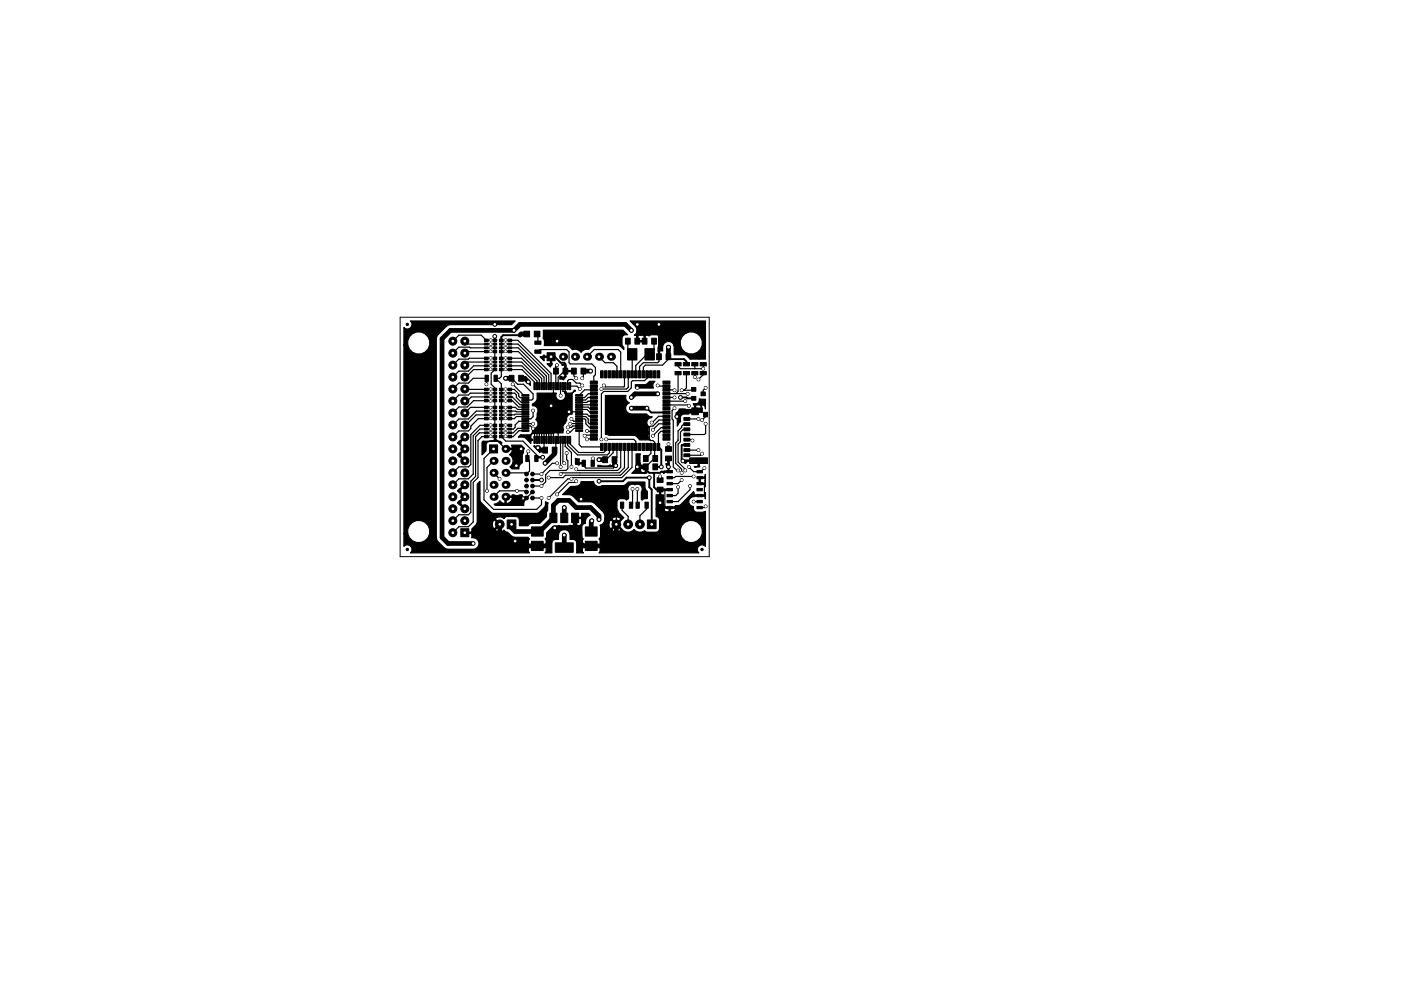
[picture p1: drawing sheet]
<svg xmlns="http://www.w3.org/2000/svg" width="297mm" height="210mm" viewBox="0 0 297 210" stroke-linecap="round" stroke-linejoin="round" font-family="sans-serif">
<path d="M84.8 67.3h65.6v50.8h-65.6z" fill="none" stroke="#000" stroke-width=".21"/>
<g fill="#000" stroke="#000" stroke-width=".21">
<path d="M102.7 75.8h.8v.5h-.8zM102.7 77.4h.8v.4h-.8zM102.7 76.6h.8v.4h-.8zM102.7 78.2h.8v.5h-.8zM102.7 72h.8v.5h-.8zM102.7 73.6h.8v.4h-.8zM102.7 72.8h.8v.4h-.8zM102.7 74.4h.8v.5h-.8zM102.8 79.6h.7v1.3h-.7zM104.5 76.6h.8v.4h-.8zM104.5 75.8h.8v.5h-.8zM104.5 77.4h.8v.4h-.8z"/>
<path d="M104.5 78.2h.8v.5h-.8zM104.5 72.8h.8v.4h-.8zM104.5 72h.8v.5h-.8zM104.5 73.6h.8v.4h-.8zM104.5 74.4h.8v.5h-.8zM104.7 79.6h.7v1.3h-.7zM105.9 77.4h.8v.4h-.8zM105.9 78.2h.8v.5h-.8zM105.9 76.6h.8v.4h-.8zM105.9 75.8h.8v.5h-.8zM105.9 73.6h.8v.4h-.8zM105.9 74.4h.8v.5h-.8z"/>
<path d="M105.9 72.8h.8v.4h-.8zM105.9 72h.8v.5h-.8zM107.7 78.2h.8v.5h-.8zM107.7 76.6h.8v.4h-.8zM107.7 77.4h.8v.4h-.8zM107.7 75.8h.8v.5h-.8zM107.7 74.4h.8v.5h-.8zM107.7 72.8h.8v.4h-.8zM107.7 73.6h.8v.4h-.8zM107.7 72h.8v.5h-.8zM111.1 70.3h1.2v1.2h-1.2zM113.3 70.3h1.2v1.2h-1.2z"/>
<path d="M113.4 74.3h1.3v.7h-1.3zM113.4 72.4h1.3v.7h-1.3zM117.4 78.1h1v1.3h-1zM116 74.8h1.7v1.7h-1.7zM119.4 78.1h1v1.3h-1zM121.2 78.1h1v1.3h-1zM123.2 78.1h1v1.3h-1zM127.3 78.7h.6v1.5h-.6zM128.1 78.7h.6v1.5h-.6zM128.9 78.7h.6v1.5h-.6zM129.7 78.7h.6v1.5h-.6zM130.5 78.7h.6v1.5h-.6z"/>
<path d="M131.3 78.7h.6v1.5h-.6zM132.1 78.7h.6v1.5h-.6zM132.6 71.8h1v1.2h-1zM132.9 78.7h.6v1.5h-.6zM133 74h2v2.4h-2zM133.7 78.7h.6v1.5h-.6zM134.5 78.7h.6v1.5h-.6zM134.6 71.8h1v1.2h-1zM135.3 78.7h.6v1.5h-.6zM136.1 78.7h.6v1.5h-.6zM136.7 74h2v2.4h-2zM136.9 78.7h.6v1.5h-.6z"/>
<path d="M136.2 71.8h1v1.2h-1zM137.7 78.7h.6v1.5h-.6zM138.5 78.7h.6v1.5h-.6zM138.2 71.8h1v1.2h-1zM139.3 78.7h.6v1.5h-.6zM139.2 75.1h1v1.2h-1zM141.2 75.1h1v1.2h-1zM143.1 76.9h1.3v.7h-1.3zM143.1 78.8h1.3v.7h-1.3zM144.9 76.9h1.3v.7h-1.3zM144.9 78.8h1.3v.7h-1.3zM146.7 76.9h1.3v.7h-1.3z"/>
<path d="M146.7 78.8h1.3v.7h-1.3zM148.4 76.9h1.3v.7h-1.3zM148.4 78.8h1.3v.7h-1.3zM102.7 86.2h.8v.5h-.8zM102.7 87.8h.8v.4h-.8zM102.7 87h.8v.4h-.8zM102.7 88.6h.8v.5h-.8zM102.7 82.4h.8v.5h-.8zM102.7 84h.8v.4h-.8zM102.7 83.2h.8v.4h-.8zM102.7 84.8h.8v.5h-.8zM102.7 90h.8v.5h-.8z"/>
<path d="M102.7 91.6h.8v.4h-.8zM102.7 90.8h.8v.4h-.8zM102.7 92.4h.8v.5h-.8zM103.8 94.4h1.7v1.7h-1.7zM104.5 87h.8v.4h-.8zM104.5 86.2h.8v.5h-.8zM104.5 87.8h.8v.4h-.8zM104.5 88.6h.8v.5h-.8zM104.5 83.2h.8v.4h-.8zM104.5 82.4h.8v.5h-.8zM104.5 84h.8v.4h-.8zM104.5 84.8h.8v.5h-.8z"/>
<path d="M104.5 90.8h.8v.4h-.8zM104.5 90h.8v.5h-.8zM104.5 91.6h.8v.4h-.8zM104.5 92.4h.8v.5h-.8zM105.9 87.8h.8v.4h-.8zM105.9 88.6h.8v.5h-.8zM105.9 87h.8v.4h-.8zM105.9 86.2h.8v.5h-.8zM105.9 84h.8v.4h-.8zM105.9 84.8h.8v.5h-.8zM105.9 83.2h.8v.4h-.8zM105.9 82.4h.8v.5h-.8z"/>
<path d="M105.9 91.6h.8v.4h-.8zM105.9 92.4h.8v.5h-.8zM105.9 90.8h.8v.4h-.8zM105.9 90h.8v.5h-.8zM108 79.6h1v1.3h-1zM107.7 88.6h.8v.5h-.8zM107.7 87h.8v.4h-.8zM107.7 87.8h.8v.4h-.8zM107.7 86.2h.8v.5h-.8zM107.7 84.8h.8v.5h-.8zM107.7 83.2h.8v.4h-.8zM107.7 84h.8v.4h-.8z"/>
<path d="M107.7 82.4h.8v.5h-.8zM107.7 92.4h.8v.5h-.8zM107.7 90.8h.8v.4h-.8zM107.7 91.6h.8v.4h-.8zM107.7 90h.8v.5h-.8zM110 79.6h1v1.3h-1zM110.6 83.7h1.5v.3h-1.5zM110.6 84.2h1.5v.3h-1.5zM110.6 84.7h1.5v.3h-1.5zM110.6 85.2h1.5v.3h-1.5zM110.6 85.7h1.5v.3h-1.5zM110.6 86.2h1.5v.3h-1.5z"/>
<path d="M110.6 86.7h1.5v.3h-1.5zM110.6 87.2h1.5v.3h-1.5zM110.6 87.7h1.5v.3h-1.5zM110.6 88.2h1.5v.3h-1.5zM110.6 88.7h1.5v.3h-1.5zM110.6 89.2h1.5v.3h-1.5zM110.6 89.7h1.5v.3h-1.5zM110.6 90.2h1.5v.3h-1.5zM110.6 90.7h1.5v.3h-1.5zM110.6 91.2h1.5v.3h-1.5zM111.5 96.6h.7v1.3h-.7zM113.2 92.6h.3v1.5h-.3z"/>
<path d="M113.2 81.2h.3v1.5h-.3zM113.7 92.6h.3v1.5h-.3zM113.7 81.2h.3v1.5h-.3zM113.4 96.6h.7v1.3h-.7zM114.2 92.6h.3v1.5h-.3zM114.2 81.2h.3v1.5h-.3zM114.7 92.6h.3v1.5h-.3zM114.7 81.2h.3v1.5h-.3zM115.2 92.6h.3v1.5h-.3zM115.2 81.2h.3v1.5h-.3zM115.7 92.6h.3v1.5h-.3zM115.7 81.2h.3v1.5h-.3z"/>
<path d="M115.1 94.9h1v1.2h-1zM116.2 92.6h.3v1.5h-.3zM116.2 81.2h.3v1.5h-.3zM116.7 92.6h.3v1.5h-.3zM116.7 81.2h.3v1.5h-.3zM117.2 92.6h.3v1.5h-.3zM117.2 81.2h.3v1.5h-.3zM117.7 92.6h.3v1.5h-.3zM117.7 81.2h.3v1.5h-.3zM117.1 94.9h1v1.2h-1zM118.2 92.6h.3v1.5h-.3zM118.2 81.2h.3v1.5h-.3z"/>
<path d="M118.7 92.6h.3v1.5h-.3zM118.7 81.2h.3v1.5h-.3zM119.2 92.6h.3v1.5h-.3zM119.2 81.2h.3v1.5h-.3zM119.7 92.6h.3v1.5h-.3zM119.7 81.2h.3v1.5h-.3zM120.2 92.6h.3v1.5h-.3zM120.2 81.2h.3v1.5h-.3zM120.7 92.6h.3v1.5h-.3zM120.7 81.2h.3v1.5h-.3zM122 91.2h1.5v.3h-1.5zM122 90.7h1.5v.3h-1.5z"/>
<path d="M122 90.2h1.5v.3h-1.5zM122 89.7h1.5v.3h-1.5zM122 89.2h1.5v.3h-1.5zM122 88.7h1.5v.3h-1.5zM122 88.2h1.5v.3h-1.5zM122 87.7h1.5v.3h-1.5zM122 87.2h1.5v.3h-1.5zM122 86.7h1.5v.3h-1.5zM122 86.2h1.5v.3h-1.5zM122 85.7h1.5v.3h-1.5zM122 85.2h1.5v.3h-1.5zM122 84.7h1.5v.3h-1.5z"/>
<path d="M122 84.2h1.5v.3h-1.5zM122 83.7h1.5v.3h-1.5zM123.4 97.6h.7v1.3h-.7zM125.3 97.6h.7v1.3h-.7zM125.2 80.8h1.5v.6h-1.5zM125.2 81.6h1.5v.6h-1.5zM125.2 82.4h1.5v.6h-1.5zM125.2 83.2h1.5v.6h-1.5zM125.2 84h1.5v.6h-1.5zM125.2 84.8h1.5v.6h-1.5zM125.2 85.6h1.5v.6h-1.5zM125.2 86.4h1.5v.6h-1.5z"/>
<path d="M125.2 87.2h1.5v.6h-1.5zM125.2 88h1.5v.6h-1.5zM125.2 88.8h1.5v.6h-1.5zM125.2 89.6h1.5v.6h-1.5zM125.2 90.4h1.5v.6h-1.5zM125.2 91.2h1.5v.6h-1.5zM125.2 92h1.5v.6h-1.5zM125.2 92.8h1.5v.6h-1.5zM127.3 94.1h.6v1.5h-.6zM127.8 96.9h1v1.3h-1zM128.1 94.1h.6v1.5h-.6zM128.9 94.1h.6v1.5h-.6z"/>
<path d="M129.7 94.1h.6v1.5h-.6zM129.8 96.9h1v1.3h-1zM130.5 94.1h.6v1.5h-.6zM131.3 94.1h.6v1.5h-.6zM132.1 94.1h.6v1.5h-.6zM132.9 94.1h.6v1.5h-.6zM133.7 94.1h.6v1.5h-.6zM134.5 94.1h.6v1.5h-.6zM135.3 94.1h.6v1.5h-.6zM136.1 94.1h.6v1.5h-.6zM136.4 96.7h1v1.2h-1zM136.9 94.1h.6v1.5h-.6z"/>
<path d="M136.4 98.4h1v1.3h-1zM137.7 94.1h.6v1.5h-.6zM138.4 96.7h1v1.2h-1zM138.5 94.1h.6v1.5h-.6zM139.3 94.1h.6v1.5h-.6zM138.4 98.4h1v1.3h-1zM141.1 94.8h1.3v1h-1.3zM141.1 96.8h1.3v1h-1.3zM141.4 99.8h1.2v.5h-1.2zM140.6 92.8h1.5v.6h-1.5zM140.6 92h1.5v.6h-1.5zM140.6 91.2h1.5v.6h-1.5z"/>
<path d="M140.6 90.4h1.5v.6h-1.5zM140.6 89.6h1.5v.6h-1.5zM140.6 88.8h1.5v.6h-1.5zM140.6 88h1.5v.6h-1.5zM140.6 87.2h1.5v.6h-1.5zM140.6 86.4h1.5v.6h-1.5zM140.6 85.6h1.5v.6h-1.5zM140.6 84.8h1.5v.6h-1.5zM140.6 84h1.5v.6h-1.5zM140.6 83.2h1.5v.6h-1.5zM140.6 82.4h1.5v.6h-1.5zM140.6 81.6h1.5v.6h-1.5z"/>
<path d="M140.6 80.8h1.5v.6h-1.5zM145 88.6h1.2v.6h-1.2zM145 89.7h1.2v.6h-1.2zM145 90.8h1.2v.6h-1.2zM145 91.9h1.2v.6h-1.2zM145 93h1.2v.6h-1.2zM145 94.1h1.2v.6h-1.2zM145 95.2h1.2v.6h-1.2zM145 96.3h1.2v.6h-1.2zM146.6 82.2h.9v.8h-.9zM146.6 84.1h.9v.8h-.9zM147.8 99.8h1.1v.5h-1.1z"/>
<path d="M146.7 86.5h1.4v1.5h-1.4zM148.6 83.2h.9v.8h-.9zM148.3 86.5h.6v1h-.6zM146.2 97.1h3.8v1.2h-3.8zM149.2 87.5h.8v.9h-.8zM97.7 112.2h1.7v1.7h-1.7zM107.5 110.3h1.9v1.9h-1.9zM112.7 111.8h2.5v1.9h-2.5zM112.7 114.8h2.5v2h-2.5zM116.6 108.9h1.5v2h-1.5zM117.7 115.2h3.8v2h-3.8zM118.9 108.9h1.5v2h-1.5z"/>
<path d="M121.2 108.9h1.5v2h-1.5zM124.1 111.8h2.5v1.9h-2.5zM124.1 114.8h2.5v2h-2.5zM131.5 106.5h.7v1.3h-.7zM133.4 106.5h.7v1.3h-.7zM134.8 106.5h.7v1.3h-.7zM136.7 106.5h.7v1.3h-.7zM137.3 110.3h1.8v1.9h-1.8zM139.3 101.4h1.3v1h-1.3zM139.3 103.4h1.3v1h-1.3zM141.4 101.1h1.2v.5h-1.2zM141.4 102.4h1.2v.5h-1.2z"/>
<path d="M141.4 103.6h1.2v.5h-1.2zM141.4 104.9h1.2v.5h-1.2zM141.4 106.2h1.2v.5h-1.2zM141.4 107.4h1.2v.5h-1.2zM147.8 107.4h1.1v.5h-1.1zM147.8 106.2h1.1v.5h-1.1zM147.8 103.6h1.1v.5h-1.1zM147.8 102.4h1.1v.5h-1.1zM147.8 101.1h1.1v.5h-1.1zM147.8 104.9h1.1v.5h-1.1z"/>
<circle cx="86.4" cy="68.8" r=".25"/>
<circle cx="96" cy="74.9" r=".85"/>
<circle cx="96" cy="72.4" r=".85"/>
<circle cx="96" cy="77.5" r=".85"/>
<circle cx="98.6" cy="72.4" r=".85"/>
<circle cx="98.6" cy="74.9" r=".85"/>
<circle cx="98.6" cy="77.5" r=".85"/>
<circle cx="104" cy="72.1" r=".25"/>
<circle cx="104" cy="78.4" r=".25"/>
<circle cx="104" cy="73.8" r=".25"/>
<circle cx="104" cy="73" r=".25"/>
<circle cx="104" cy="75.9" r=".25"/>
<circle cx="104" cy="74.5" r=".25"/>
<circle cx="104" cy="77.6" r=".25"/>
<circle cx="104" cy="76.8" r=".25"/>
<circle cx="104.9" cy="71.4" r=".4"/>
<circle cx="104.9" cy="68.8" r=".4"/>
<circle cx="107.2" cy="75.9" r=".25"/>
<circle cx="107.2" cy="73.8" r=".25"/>
<circle cx="107.2" cy="76.8" r=".25"/>
<circle cx="107.2" cy="77.6" r=".25"/>
<circle cx="107.2" cy="73" r=".25"/>
<circle cx="107.2" cy="72.1" r=".25"/>
<circle cx="107.2" cy="74.5" r=".25"/>
<circle cx="107.2" cy="78.4" r=".25"/>
<circle cx="109" cy="70.1" r=".4"/>
<circle cx="118.1" cy="77.5" r=".3"/>
<circle cx="118.1" cy="72.4" r=".3"/>
<circle cx="125.2" cy="78.7" r=".4"/>
<circle cx="133.9" cy="70.1" r=".4"/>
<circle cx="135.1" cy="68.8" r=".4"/>
<circle cx="139.7" cy="68.8" r=".4"/>
<circle cx="141.7" cy="73.7" r=".4"/>
<circle cx="149.1" cy="78.2" r=".3"/>
<circle cx="96" cy="80" r=".85"/>
<circle cx="96" cy="87.6" r=".85"/>
<circle cx="96" cy="92.7" r=".85"/>
<circle cx="96" cy="90.2" r=".85"/>
<circle cx="96" cy="97.8" r=".85"/>
<circle cx="96" cy="82.5" r=".85"/>
<circle cx="96" cy="95.2" r=".85"/>
<circle cx="96" cy="85.1" r=".85"/>
<circle cx="98.6" cy="85.1" r=".85"/>
<circle cx="98.6" cy="92.7" r=".85"/>
<circle cx="98.6" cy="80" r=".85"/>
<circle cx="98.6" cy="97.8" r=".85"/>
<circle cx="98.6" cy="82.5" r=".85"/>
<circle cx="98.6" cy="87.6" r=".85"/>
<circle cx="98.6" cy="90.2" r=".85"/>
<circle cx="98.6" cy="95.2" r=".85"/>
<circle cx="103.1" cy="81.5" r=".3"/>
<circle cx="104" cy="88" r=".25"/>
<circle cx="104" cy="88.8" r=".25"/>
<circle cx="104" cy="84.2" r=".25"/>
<circle cx="104" cy="82.5" r=".25"/>
<circle cx="104" cy="92.6" r=".25"/>
<circle cx="104" cy="83.4" r=".25"/>
<circle cx="104" cy="91.1" r=".25"/>
<circle cx="104" cy="85.1" r=".25"/>
<circle cx="104" cy="91.8" r=".25"/>
<circle cx="104" cy="86.5" r=".25"/>
<circle cx="104" cy="90.2" r=".25"/>
<circle cx="104" cy="87.2" r=".25"/>
<circle cx="107.2" cy="92.6" r=".25"/>
<circle cx="107.2" cy="88" r=".25"/>
<circle cx="107.2" cy="91.8" r=".25"/>
<circle cx="107.2" cy="88.8" r=".25"/>
<circle cx="107.2" cy="86.5" r=".25"/>
<circle cx="107.2" cy="83.4" r=".25"/>
<circle cx="107.2" cy="91.1" r=".25"/>
<circle cx="107.2" cy="90.2" r=".25"/>
<circle cx="107.2" cy="87.2" r=".25"/>
<circle cx="107.2" cy="85.1" r=".25"/>
<circle cx="107.2" cy="84.2" r=".25"/>
<circle cx="107.2" cy="82.5" r=".25"/>
<circle cx="107.2" cy="80.3" r=".4"/>
<circle cx="108.7" cy="81.5" r=".3"/>
<circle cx="109.5" cy="98.8" r=".3"/>
<circle cx="110.5" cy="95.2" r=".3"/>
<circle cx="112" cy="81" r=".4"/>
<circle cx="112" cy="95.8" r=".3"/>
<circle cx="113" cy="87.1" r=".3"/>
<circle cx="113" cy="89.9" r=".3"/>
<circle cx="113" cy="90.9" r=".3"/>
<circle cx="114" cy="95" r=".4"/>
<circle cx="115.1" cy="97" r=".4"/>
<circle cx="115.6" cy="98.3" r=".4"/>
<circle cx="116.8" cy="86.1" r=".3"/>
<circle cx="118.1" cy="98.3" r=".3"/>
<circle cx="118.9" cy="99.1" r=".3"/>
<circle cx="118.9" cy="83.9" r=".3"/>
<circle cx="119.6" cy="98.3" r=".3"/>
<circle cx="120.1" cy="96.1" r=".3"/>
<circle cx="120.4" cy="91.7" r=".3"/>
<circle cx="120.4" cy="90.7" r=".3"/>
<circle cx="120.7" cy="87.4" r=".3"/>
<circle cx="120.9" cy="89.9" r=".3"/>
<circle cx="121.2" cy="99.1" r=".3"/>
<circle cx="121.2" cy="88.9" r=".3"/>
<circle cx="122.2" cy="99.6" r=".3"/>
<circle cx="122.2" cy="80.3" r=".3"/>
<circle cx="122.9" cy="82.5" r=".3"/>
<circle cx="123.4" cy="80.3" r=".3"/>
<circle cx="123.4" cy="81.8" r=".3"/>
<circle cx="124" cy="92.5" r=".3"/>
<circle cx="124.5" cy="93.2" r=".3"/>
<circle cx="124.5" cy="91.4" r=".3"/>
<circle cx="125.7" cy="97.3" r=".3"/>
<circle cx="127" cy="97.5" r=".4"/>
<circle cx="127.5" cy="93.2" r=".3"/>
<circle cx="127.5" cy="82.5" r=".3"/>
<circle cx="128" cy="81.8" r=".3"/>
<circle cx="128.5" cy="93.2" r=".3"/>
<circle cx="130.6" cy="98.8" r=".4"/>
<circle cx="133.9" cy="84.3" r=".4"/>
<circle cx="133.9" cy="86.6" r=".4"/>
<circle cx="135.1" cy="99.1" r=".4"/>
<circle cx="135.1" cy="82.3" r=".3"/>
<circle cx="137.2" cy="86.6" r=".4"/>
<circle cx="138.2" cy="89.7" r=".3"/>
<circle cx="138.4" cy="91.2" r=".3"/>
<circle cx="138.4" cy="92.5" r=".3"/>
<circle cx="139.4" cy="83.6" r=".4"/>
<circle cx="139.4" cy="81.8" r=".3"/>
<circle cx="140.2" cy="99.1" r=".4"/>
<circle cx="141.7" cy="99.1" r=".4"/>
<circle cx="141.7" cy="94.2" r=".3"/>
<circle cx="143" cy="86.6" r=".3"/>
<circle cx="143" cy="82.8" r=".3"/>
<circle cx="143" cy="84.3" r=".3"/>
<circle cx="143.5" cy="88.4" r=".4"/>
<circle cx="143.8" cy="99.8" r=".3"/>
<circle cx="144.3" cy="84.3" r=".4"/>
<circle cx="144.5" cy="82.8" r=".3"/>
<circle cx="144.8" cy="97.8" r=".4"/>
<circle cx="145.3" cy="85.1" r=".3"/>
<circle cx="145.3" cy="99.8" r=".3"/>
<circle cx="145.8" cy="83.6" r=".3"/>
<circle cx="146.1" cy="99.1" r=".3"/>
<circle cx="146.1" cy="86.1" r=".3"/>
<circle cx="146.8" cy="93.5" r=".3"/>
<circle cx="147.3" cy="80" r=".3"/>
<circle cx="148.1" cy="95.5" r=".3"/>
<circle cx="148.1" cy="88.9" r=".3"/>
<circle cx="148.1" cy="80.5" r=".3"/>
<circle cx="148.8" cy="96.3" r=".3"/>
<circle cx="148.8" cy="89.1" r=".3"/>
<circle cx="149.4" cy="99.3" r=".3"/>
<circle cx="149.6" cy="89.9" r=".3"/>
<circle cx="149.6" cy="82.3" r=".3"/>
<circle cx="86.4" cy="116.6" r=".25"/>
<circle cx="96" cy="100.3" r=".85"/>
<circle cx="96" cy="110.5" r=".85"/>
<circle cx="96" cy="107.9" r=".85"/>
<circle cx="96" cy="105.4" r=".85"/>
<circle cx="96" cy="113" r=".85"/>
<circle cx="96" cy="102.9" r=".85"/>
<circle cx="98.6" cy="107.9" r=".85"/>
<circle cx="98.6" cy="110.5" r=".85"/>
<circle cx="98.6" cy="100.3" r=".85"/>
<circle cx="98.6" cy="105.4" r=".85"/>
<circle cx="98.6" cy="102.9" r=".85"/>
<circle cx="100.3" cy="115.3" r=".3"/>
<circle cx="103.3" cy="104.1" r=".3"/>
<circle cx="105.9" cy="101.6" r=".3"/>
<circle cx="106" cy="111.2" r=".92"/>
<circle cx="109.2" cy="114.8" r=".3"/>
<circle cx="109.6" cy="104.1" r=".3"/>
<circle cx="111.6" cy="105.7" r=".39"/>
<circle cx="111.6" cy="101.8" r=".39"/>
<circle cx="111.6" cy="104.4" r=".39"/>
<circle cx="111.6" cy="100.6" r=".39"/>
<circle cx="111.6" cy="103.1" r=".39"/>
<circle cx="112.9" cy="100.6" r=".39"/>
<circle cx="112.9" cy="105.7" r=".39"/>
<circle cx="112.9" cy="103.1" r=".39"/>
<circle cx="112.9" cy="101.8" r=".39"/>
<circle cx="112.9" cy="104.4" r=".39"/>
<circle cx="114.8" cy="101.8" r=".4"/>
<circle cx="114.8" cy="103.1" r=".3"/>
<circle cx="114.8" cy="105.7" r=".3"/>
<circle cx="114.8" cy="100.6" r=".3"/>
<circle cx="116.3" cy="101.3" r=".3"/>
<circle cx="116.3" cy="105.7" r=".3"/>
<circle cx="117.6" cy="112" r=".3"/>
<circle cx="118.1" cy="104.9" r=".3"/>
<circle cx="118.9" cy="100.6" r=".3"/>
<circle cx="119.6" cy="113.5" r=".4"/>
<circle cx="119.6" cy="107.7" r=".4"/>
<circle cx="121.2" cy="101.6" r=".3"/>
<circle cx="122.2" cy="102.1" r=".3"/>
<circle cx="123.2" cy="105.9" r=".3"/>
<circle cx="125.5" cy="110.5" r=".4"/>
<circle cx="127" cy="110.2" r=".4"/>
<circle cx="127" cy="102.1" r=".4"/>
<circle cx="130.7" cy="111.2" r=".92"/>
<circle cx="133.2" cy="111.2" r=".92"/>
<circle cx="134.1" cy="103.8" r=".3"/>
<circle cx="135.1" cy="103.8" r=".3"/>
<circle cx="135.7" cy="111.2" r=".92"/>
<circle cx="137.7" cy="101.3" r=".4"/>
<circle cx="140" cy="101.1" r=".3"/>
<circle cx="140" cy="106.7" r=".3"/>
<circle cx="143.8" cy="103.4" r=".3"/>
<circle cx="144.5" cy="101.8" r=".3"/>
<circle cx="144.5" cy="100.3" r=".3"/>
<circle cx="146.3" cy="103.1" r=".3"/>
<circle cx="147.1" cy="101.1" r=".3"/>
<circle cx="147.1" cy="106.4" r=".3"/>
<circle cx="148.8" cy="116.6" r=".25"/>
<circle cx="149.6" cy="107.4" r=".3"/>
</g>
<g fill="#000">
<circle cx="119.4" cy="75.7" r=".85"/>
<circle cx="121.9" cy="75.7" r=".85"/>
<circle cx="124.5" cy="75.7" r=".85"/>
<circle cx="127" cy="75.7" r=".85"/>
<circle cx="129.5" cy="75.7" r=".85"/>
<circle cx="104.6" cy="97.8" r=".85"/>
<circle cx="107.2" cy="95.2" r=".85"/>
<circle cx="107.2" cy="97.8" r=".85"/>
<circle cx="104.6" cy="100.3" r=".85"/>
<circle cx="104.6" cy="102.9" r=".85"/>
<circle cx="104.6" cy="105.4" r=".85"/>
<circle cx="107.2" cy="105.4" r=".85"/>
<circle cx="107.2" cy="102.9" r=".85"/>
<circle cx="107.2" cy="100.3" r=".85"/>
</g>
<path d="M115.1 97h-1.1l-.3 .3" fill="none" stroke="#000" stroke-width=".5"/>
<g fill="none" stroke="#000" stroke-width=".25">
<path d="M98.6 72.4l.6 .6h4.8M104 77.6h-3.6l-1.1 1.1h-2l-1.3 1.3M104 73.8l-6.7-.1-1.3 1.2M104 76.8h.1M104 76.8h-4.8l-.6 .7M104 74.5l-5.1 .1-.3 .3M104 78.4h-3.6l-1.6 1.6h-.2M104 77.6h.1M104 75.9l-6.7 .3-1.3 1.3M104 73.8h.1M104 72.1l-.9 .1-1.1-1.1h-4.7l-1.3 1.3M104.9 72.2v6.2l-.8 .8v2.3l.8 .8v10.7l2.3 2.2"/>
<path d="M106.3 72.2v7.7l-.4 .4h-.8l1.2 1.2v11.1l.9 1h3.7l2.8 2.8v.9M107.2 73h2.6l6.5 6.5v2.4M107.2 74.5l2.7 .1 5.4 5.4v1.9M107.2 72.1l2.6 .1 7 7v2.7M107.2 73.8h2.7l5.9 6v2.1M107.2 75.9l3.4 .1 4.2 4.3v1.6M107.2 76.8h3.4l3.7 3.8v1.3M107.2 77.6h3.4l3.2 3.2v1.1M107.2 78.4h3.5l2.6 2.7v.8M113.9 70.9l.1 .1v1.7M114 74.6l.5-.4h5.6l.5 .5v2.3l.3 .2h4.6l.7 .8v1.5l-.3 .3v1.3M117.9 78.7l-.1 3.2"/>
<path d="M119.9 78.7h-.3l-1.3 1.3v1.9M121.7 78.7v1.1l.5 .5M123.7 78.7v1.3l-.3 .3M124.5 75.7l1.5-1.5h5.1l.5 .5v4.7M127 75.7l1.3 1.3h1.7l.8 .7v1.7M132.4 79.4v2.6l-.1 .1h-4l-.3-.3M133.1 72.4v1.9l.9 .9v4.2M133.2 79.4v2.8l-.4 .3h-5.3M137.2 79.4v.8l-.5 .6h-2.6l-.2 .2v1.3l-.8 .8h-5.1l-.5 .5v9.6M138.7 72.4v1.9l-1 .9h-.5l-2.4 2.3v1.9M139.7 75.7v1l-.3 .3h-3l-.8 .8v1.6M141.7 75.7v.5l-1.2 1.3h-3.7l-.4 .4v1.5"/>
<path d="M143.8 77.3v.4l.5 .5h4.8v-.9M143.8 79.2v3.9l-.5 .4M145.5 79.2v3.1l-.5 .5M147.3 77.3v.9M147.3 79.2v.8M149.1 79.2v.3l-1 1M98.6 82.5h5.4M103.1 81.5l.1-1.2h-2.9l-1 1h-2l-1.3 1.2M104 87.2h-3l-1.7 1.7h-2l-1.3 1.3M104 87.2h.1M104 83.4h-4.3l-.4 .4h-2l-1.3 1.3M104 83.4h.1"/>
<path d="M104 86.5l-4.2-.1-1.2 1.2M104 90.2h-2.2l-2 2v6.3l-.5 .6h-2l-1.3 1.2M104 92.6h-1.8l-.9 .9v7.8l-1 1.1v8.3l-1 1.1h-2l-1.3 1.2M104 91.1l-2.3-.1-1.4 1.5v8.1l-1 1h-2l-1.3 1.3M104 91.8h-2.3l-.9 .8v8.5l-1 1v6.6l-.5 .5h-2l-1.3 1.3M104 88.8h-2.6l-1.6 1.6v.5l-.5 .5h-2l-1.3 1.3M104 88h-3.1l-2.1 2.2h-.2M104 84.2h-4.1l-.8 .9h-.5M104 85.1l-3.6-.1-1.3 1.4h-1.8l-1.3 1.2M104.6 95.2l-2 2.1v8.7l2 2.1h9.2l1-1v-1.4h-1.9M104.6 97.8l-1.3 1.4v4.9M107.2 87.2l4.2 .2"/>
<path d="M107.2 83.4h1.9l.4 .4v.5l1 1.1h.9M107.2 82.5l1.8 .1 1 1v.5l.3 .3h1.1M107.2 84.2h1.4l1.7 1.7h1.1M107.2 85.1l1.4-.1 1.4 1.4h1.4M107.2 86.5l2.1-.1 .4 .5h1.7M107.2 90.2h.9M108.5 80.3l1.2 1.2h1.3l2 2.1v1l-.3 .3h-1.3M108.7 81.5l2.4 2.4h.3M110 89.4h1.4M110 89.4h.1M110 89.4l-.8 .8v.5l-.3 .3-1.7 .1M110.5 95.2v2.1l-1 1v.2"/>
<path d="M111.4 90.4h1.1l.8 .8v2.1M111.4 87.9l-4.2 .1M111.4 88.4h-1.9l-.5 .4h-1.8M111.4 89.9h1.6M111.4 90.9h-1.6l-1 .9h-1.6M111.4 91.4h-1.4l-1.2 1.2h-1.6M112 95.8l-.2 .1v1.4l.5 .4v2.2l-.7 .7-.2-.3h-4.2M113 89.9h.1M113 87.1v1.3l-.5 .5h-1.1M113 90.9h5l.3 .4v2M113.8 90.9v2.4M114.3 90.9v2.4"/>
<path d="M114.8 90.9v2.4M115.3 90.9v4.4l.3 .2M115.8 90.9v2.4M116.3 90.9v2.4M116.8 90.9v2.4M117.3 81.9v2.9l.4 .4h1.8l.5-.5-.2-2.8M117.3 90.9v2.4M117.3 83.9h.1M117.8 93.3v1.9l-.2 .3M118.1 98.3h-1l-2.3 2.3h-1.9M118.8 81.9l.1 2M118.8 93.3l.1 5.8"/>
<path d="M119.3 81.9v1.2h.6M119.3 93.3v4.7l.3 .3M119.6 83.1l.4 .3M119.8 93.3l.1 1.4M119.8 94.7l1.4 1.3v3.1M120.1 96.1v1.4l.3 .3v1.6l-.4 .4h-3.4l-.9 .9v1.5l-.9 .9h-1.9M120.3 93.3v1.1l2.1 2.1h6.4l.4-.4v-1.3M120.6 87.4h.1M120.7 87.4h2.1M120.8 81.9h1.5l.6 .6M120.8 93.3v.9l1.9 1.8h5.3l.4-.4v-.8M121.2 88.9l.4 .5h1.2"/>
<path d="M122.8 87.9h1.7l.4 .4h1M122.8 90.4h-1.3l-.3 .3h-.8M122.8 85.9h3.1M122.8 86.4h1.9l.4 .3h.8M122.8 86.9h1.7l.6 .6h.8M122.8 88.4h1.4l.5 .5v.8l.3 .2h.9M122.8 89.9h-1.9M122.8 88.9h1.2l.2 .2v.8l.8 .8h.9M122.8 90.9h-1.1l-.8 .8h-.5M122.8 91.4v2.9l.5 .5h4.3M123.4 81.8l-.5-.5h-.7l-.8-.8h-.8l-.3 .3v1.1M123.8 98.3v.6l.4 .4h5.8l.6-.5"/>
<path d="M124.5 91.4l1.4 .1M125.7 97.3v1M125.9 92.3h-1.8l-.1 .2M125.9 84.3h-1.2l-.5 .6h-1.4M125.9 85.1h-1.2l-.3 .3h-1.6M125.9 83.5h-1.1l-.9 .9h-1.1M125.9 82.7h-1.9l-1.2 1.2M125.9 93.1l-1.4 .1M128.5 93.2h5.9l.4 .5v1.1M130 94.8v1.3l-1.5 1.4h-.2M130.8 94.8v2.2l-.5 .5M131.6 94.8v4.3l-.7 .7h-8.5l-.2-.2"/>
<path d="M132.4 94.8v4.4l-1.1 1.1h-12.2l-.2 .3M133.2 94.8v4.4l-1.6 1.6h-11.7l-.5 .5h-3.1M134 94.8v4.4l-2.2 2.1h-10.4l-.2 .3h-.8l-4.1 4.1M138 94.8v1.4l-1.1 1.1M139.4 81.8l.2 .1h1.7M141.3 91.5h-1.2l-.5 .5v2.8M141.3 89.1h-1.6l-1.3 1.3h-.5l-.2 .3v2.5l.2 .3h.5l.4 .3v3.4l.1 .1h-.2l-1.8 1.8M141.3 85.9h4.6l.1 .2M141.3 84.3h1.7M141.3 89.9h-1.6l-1.3 1.3M141.3 83.5l4.5 .1M141.3 82.7l1.7 .1"/>
<path d="M141.3 88.3h-1.7l-1.4 1.4M141.3 90.7h-1.1l-1.8 1.8M141.7 94.2v1.1M143 84.3h.1M143 86.6l-.5 .5v1.8l.2 .2v10l.8 .7h.3M145.3 85.1h-4M145.6 91.1h-.7l-.6 .6v2l-.5 .5v3.8l1.5 1.6v.2M145.6 90h-.6l-1.2 1.4v2.1l-.5 .5v4.3l1.2 1.3v.7M145.6 95.5h2.5M145.6 88.9h2.5M145.6 93.3h1l.2 .2M146 99.1l1.1 1h1.5l.8-.8"/>
<path d="M147.1 82.6l-.2 .2h-2.4M148.1 88.9h.1M148.6 87h-1l-.2 .3M148.8 96.3l-.3 .3h-2.9M149.6 88v.4l-.8 .7M149.6 89.9v2l-.2 .3h-3.8M149.6 82.3l-.5 .5v.8M104.6 100.3l1.3 1.3M109.2 114.8v1M111.6 104.4l-.2-.3h-5.5l-1.3 1.3M112.9 104.4l-1.3 1.3-.2-.3h-4.2M122.2 102.1l-.3 .3h-1.3l-2.5 2.5"/>
<path d="M123.2 105.9h4.8l2.7 2.7v2.6M131.9 107.2v1.1l1.3 1.2v1.7M134.1 103.8v3.1l-.3 .3M135.1 103.8v3.3l.3-.1M137.1 107.2v.8l-1.4 1.4v1.8M140 101.1v.8M141.2 103.9l-.2 .2v3.3l.2 .3h.8M142 103.9h-2v2.8M143.8 103.4v1.2l-.5 .6h-1.3M144.5 101.8l-.7 .8h-1.8M146.3 103.1v.8l-2.5 2.5h-1.8M147.1 101.1h-3.8l-.3 .2h-1"/>
<path d="M147.1 106.4h1.2M148.3 101.3v1.3h.8l.3 .3v2l-.3 .3h-.8M149.6 107.4h.1M149.6 107.4l-.2 .3h-1.1"/>
</g>
<g fill="none" stroke="#000" stroke-width=".4">
<path d="M104.9 71.4v.8M110.2 71.1h-3.5l-.4 .4v.7M116.8 75.7h.8l1.3 1.3h.7l.3 .2v1.5h1.8M116.8 75.7h.1M118.1 77.5l-.2 .2v1M135.1 68.8v3.6h1.6M135.1 68.8h.1M139.7 68.8h.1M139.7 68.8v6.9M141.7 75.7l.5 .5h2.8l.5 .5v.6M137.2 86.6l.9 .9h3.2M139.6 94.8l.6 .6v3.7h-1.3"/>
<path d="M141.7 97.3v2.5l.3 .3h-1.8l-.2 .2h-2.3l-.8-.7v-.5M144.3 84.3l2.8 .2M145.6 94.4l-1.1 .1v3l.3 .3 3.3-.1M112.9 101.8h1.9M127 102.1h5.1l.7-.8h4.9v2.1l.5 .5v7.3M138.7 100.3v3.1l.5 .5h.8M148.3 105.2h-1.5l-2.5 2.5h-2.3"/>
</g>
<g fill="none" stroke="#000" stroke-width="1">
<path d="M111.7 70.9h-1.2l-.3 .2M123.7 78.7h1.5M133.9 70.1l-1.3-1.3h-22.4l-1.2 1.3h-13.5l-1.8 1.8v42.1l1.3 1.3h5.3M141.7 73.7v2M141.7 73.7h.1M107.2 80.3h1.3M110.5 80.3h.8l.7 .7M114 95l.6 .5h1M117.6 95.5v.8l-2 2M127 97.5h1.3M130.3 97.5v1l.3 .3M133.9 86.6h3.3"/>
<path d="M135.1 99.1h1.8M139.4 83.6h-4.8l-.7 .7M147.4 87.3h-2.8l-1.1 1.1M106 111.2v3.6l.9 1h8.9l.8-.7v-2.1l1-1h4.6M119.6 107.7v2.2M119.6 113.5v2.7M121.9 109.9v1.9l1 1v2.3l.8 .7h6.3l.7-.6v-4M125.5 110.5l-.2 .1v2.2M127 110.2v-.7l-1.8-1.8h-3l-1.6-1.5h-2.2l-1.1 1v2.7l-2.9 2.9h-5.2l-.7-.8v-.8"/>
</g>
<g fill="#000" stroke="#000" stroke-width=".25">
<path d="M85.6 69.5a.98 .98 0 0 0 1.5 0 .98 .98 0 0 0-.1-1.4h22.2l-.7 .8-13.5 .1-2.1 2-.4 .9v42.1l.4 .9 1.6 1.5 5.8 .1a1.25 1.25 0 0 0 1.2-1.4 1.25 1.25 0 0 0-1.5-1v-.8l-.1-.1h-1.5v-.3h1.5l.1-.2v-.5l1.1-1.2h3.3v.6l.2 .5 .3 .1 .9-1-.9-.9-.3 .1-.2 .6h-3.3l.1-8.3 .6-.6v4.3l2.5 2.5h9.5a2.85 2.85 0 0 0 1.8-1.5l.1-1 .5 .3-.4 2.9-1.4 1.5h-2l-.4 .4h-1.9v-1.2a.74 .74 0 0 0-.7-.7h-1.9l-.5 .2-.2 .3v-.2a1.18 1.18 0 0 0-1.8 .2l1.2 1.1-1.2 1.1a1.12 1.12 0 0 0 1.8 .1l1.9 1.5 3.3 .1 .3 .3-.3 .4v.8l.2 .2h3.4l.2-.2v-.8l-.2-.4 .3-.3v-1l1.4-1.4 1.2-.1 .4 .1h1.5l.5-.2 .7 .1 .2-.1v-1.4h.3v1.4l.1 .1h.6l.5-.5v-.8l-.1-.2h-1.4v-.3h1.4l.1-.1v-.7h1.4l.4 .4-.1 .1a1.56 1.56 0 0 0-.9 1.7l-.5 .2-.2 .5v1.9l.3 .6-.2 .4v.8l.1 .2h3.5l.1-.2v-.8l-.2-.4a.96 .96 0 0 0 .3-1.1h16.9l.4 .9a2.37 2.37 0 0 0 3.9 0 2.37 2.37 0 0 0-1.5-3.7 2.37 2.37 0 0 0-2.8 2.8h-16.9v-.9h2.5v.3a1.18 1.18 0 0 0 1.8-.3l-.9-.9-.9 .9h-2.5l-.1-.9a2.65 2.65 0 0 1 1.9-.4v.6l.2 .5 .3 .1 .9-1-.9-.9-.3 .1-.2 .6h-1.2l.3-.9h1.6l.9 1 .9-1a1.09 1.09 0 0 0-1.8 0h-1.6l-.1-1.1-.2-.4-2.2-2-3-.1-1.6-1.5-1.8-.1 1.7-1.7 1.4-.1a1 1 0 0 0 .8-.9h2.7v.1a1.14 1.14 0 0 0 1.8 .7h4.4h.3l.8-.7h3.5l.1 1.4 .4 .6v1.5h-.7l-.4 .3-.1-.1v-1.6a1.04 1.04 0 0 0-.1-1.3 1.04 1.04 0 0 0-1.3-.2 1.04 1.04 0 0 0-1.3 .2 1.04 1.04 0 0 0 0 1.3v1.4l-.5 .3a1.21 1.21 0 0 0-2 .4l.1 1.6 .4 .8 1 .9-1.4 1.4 .9 1a1.65 1.65 0 0 0 2.6 .1 1.61 1.61 0 0 0 2.3 .3l.6 .3h1.8a.74 .74 0 0 0 .7-.7v-1.9l-.2-.5-.5-.2v-1.6l1.7 .1a.71 .71 0 0 0 .9 .5l.2-.2v-.6h.2v.6l.2 .2 .6-.1 .3-.5-.2-.2-3.9 .2v-3h.6l.1-.2v-1.1h2.3v.3h-2v.8l.1 .2h.5l.1 .8a2.32 2.32 0 0 0 .1 1.8h2.1l.2-.3 .9-.1 2.9-2.9 .3 .7h2.1l.2-.5v1.3l-.2-.5h-2.1l-.1 .1a1.03 1.03 0 0 0-1.2 .9 1.03 1.03 0 0 0 1 1.1 .92 .92 0 0 0 .8 1.3h1.1l.7-.2v7.4a.98 .98 0 0 0-1.5 0 .98 .98 0 0 0 .1 1.4h-21.2l.2-.4v-.8l-.1-.2h-3.5l-.1 .2v.8l.2 .4h-1.5v-2.4l-.4-.4-.9-.1a1.65 1.65 0 0 0-.8-2 1.23 1.23 0 0 0-1.7 1.1v.9h-.7a.74 .74 0 0 0-.7 .8v2.1h-1.4l.2-.4v-.8l-.2-.2h-3.4l-.2 .2v.8l.3 .4h-25.3l.2-.2a.99 .99 0 0 0-.2-1.3 .99 .99 0 0 0-1.4 .1v-2.7h.8a2.37 2.37 0 0 0 3.7 1.5 2.37 2.37 0 0 0 0-3.9 2.37 2.37 0 0 0-3.7 1.5v.9h-.8v-40h.8a2.37 2.37 0 0 0 3.7 1.5 2.37 2.37 0 0 0 0-3.9 2.37 2.37 0 0 0-3.7 1.5v.9h-.8zM114.5 75.7a.79 .79 0 0 0 .9-.4l.1 .3h1.5v1.4l.1 .2-.4 .7-.7-.7h.6l.1-.2v-1.2h-1.2l-.1 .2v.6zM119.1 77.2h.7l.3 .4-.1 1h1.8v.3h-1.8l.1 1-.6 .7-.8-.2v-.4l.2-.2a.55 .55 0 0 0 .8 0v-2.2l-.1-.1h-.5zM115.2 70.1h16.9l1 .9a.9 .9 0 0 0-1.2 .8v1.2l.4 .6v.6l-.6-.6-.6-.3h-5.1l-.6 .3-.6 .5a1.42 1.42 0 0 0-1.6 .7 1.49 1.49 0 0 0-1.9-.6 1.79 1.79 0 0 0-1.2-.9h-4.7a1.53 1.53 0 0 0-.3-1.5zM133.6 68.1h16v8.1h-3.2l-1-.9h-2.4l-.1-2.1h1.3a2.37 2.37 0 0 0 3.7 1.5 2.37 2.37 0 0 0 0-3.9 2.37 2.37 0 0 0-3.7 1.5v.9h-1.3a1.23 1.23 0 0 0-1.4-.8 1.23 1.23 0 0 0-1 1.3v.8l-.5-.1-.2 .2 .1 1.2h-.3l-.1-1.4v-.8l.2-.1a2.45 2.45 0 0 0 .2-2l-.2-.3a2 2 0 0 0-2 0l-.1 .1a.55 .55 0 0 0-.8 0v1.2h-1.8v-1.2h.2v1h1.3v-1l-.1-.2h-1l-.2 .2-.7-.2a1.19 1.19 0 0 0 .2-1.9zM97.4 93.5l.1 .1 1-1.1 .2 .2-1 1v.5l1 1-1 1.1v.4l1 1.1-.1 .2-1.6-1.5 1.4-1.3-1.4-1.2zM102.2 93.8l.2-.2 2.2-.1 .4-1v.9l.2 .1 .9 .1 .3 .4-.2 .2-.2-.3-.5-.2h-1.7a.74 .74 0 0 0-.7 .7v1.2l-.9 .9zM110.3 80.1h.3v.3h-.3zM107 95.1h1.5l.1-.2-.2-.5h2.1l.7 .7-.2 1a2.51 2.51 0 0 0-.2 2.1 1.16 1.16 0 0 0-.8 1.3h-1.5l-.4-.4a1.51 1.51 0 0 0-.1-2.6l.5-.5 .1-.4-.1-.2h-1.4zM111.6 80.6l.9 .8v.4l-.9-.9zM113.3 94.5l.3 .2h.9v.5l.1 .2h1.1v.2h-1.1l-.1 .4-1.3-1.3zM113.9 83.4h4.1a1.05 1.05 0 0 0 1 1.6 1.05 1.05 0 0 0 .7-1.7l.5 .1a1.24 1.24 0 0 0 1.5-.6h.2l.1 .2a1.25 1.25 0 0 0-.7 1.6v3.3a1.02 1.02 0 0 0-1.1 1.3l-.3 .6a1 1 0 0 0-.4 1.4l-.1 .6h-1.7l-.9 .2h-4l-.2 .4v.6l.3 .2v.3l-.3 .1v.5l-1.4-1.3-1.3-.1 .5-.5 1.7 .1a1.08 1.08 0 0 0 .8-1.4 1.04 1.04 0 0 0 1.1-.6 1.04 1.04 0 0 0-.4-1.3 1.34 1.34 0 0 0 .3-1.3 1.04 1.04 0 0 0 0-1.1 1.04 1.04 0 0 0-1-.5v-.4h.2a1.48 1.48 0 0 0 .8-1.1z"/>
<path d="M122 97.2l.8 .2v.6l.1 .2 1-.1v.3h-1l-.1 .3-.7-.2zM126.8 98.7l.7 .1a2.17 2.17 0 0 0 1.8-.1l.1-.1a.55 .55 0 0 0 .8 0l-.1-1.2h.3v1.2l.4 .2-.2 .2h-3.8zM128.4 83.9h4.3a1.2 1.2 0 0 0 .7 1.6 1.22 1.22 0 0 0-.8 1.3 1.22 1.22 0 0 0 1.3 1h3.2a1.24 1.24 0 0 0 1.2 .6l-.2 .2a1.03 1.03 0 0 0-.9 .8 1.03 1.03 0 0 0 .4 1.1 1.24 1.24 0 0 0 0 1.4 1.04 1.04 0 0 0 .3 1.4h-2.3a1.75 1.75 0 0 0-1.2-.9h-5.3l-.7-.2zM134.9 96.3h.9v2.5l.1 .1h1.2l-.1 1.3 .2 .1-3.2 .1 .8-1.1h1v.5a.61 .61 0 0 0 1 .4v-1l-2 .1zM134.7 81.6h2l.6-.2 .4-.5h1.2a1.03 1.03 0 0 0-.3 1.4h-3.9zM138.8 97.1h.2l.1 .3h-.3zM141.6 97.1h.3v2.2l-.6-.1-.2-.8 .5-.2zM140.4 100.2l.5-.3h1.2v.3h-1.2l-.1 .3zM144.6 97.5l.4 .1h3.2v1.2l.2 .2-.1 .1-.9 .1-.2-.2h.6l.2-.2v-.9h-2.2l-.5 .5-.7-.7zM145.5 94.3h.3v.1h-.3zM144 86.8h1.3l.5 .3h1.4v-1l-.2-.4a1.01 1.01 0 0 0 1.2-.5l.1-.6 1.3 .1v2a.66 .66 0 0 0-.7-.8l-.2 .2v.8v-.5l-.4-.5h-.6l-.2 .2v1.3h-1.3l-.2 .4h-1a.74 .74 0 0 0-.7 .8v.8l-.7 1v-1.3l-.3-.6v-.9l.6-.4zM98.4 110.5l.2-.2 .1 .2-.2 .2z"/>
<path d="M97.4 103.7h.1l1-1 .2 .2-1 1v.5l1 1-1 1v.5l1 1-.1 .2-1.6-1.4 1.4-1.3-1.4-1.3zM98.4 100.3l.2-.2 .1 .2-.2 .2zM104.7 107l.6-.1 .7-.7 .8 .6 .3-.1v-1.2h.2v1.2a.99 .99 0 0 0 1.2-1.2h-1.5v-.2h1.5l.1-.3h.4a1.02 1.02 0 0 0 1.2 0h.5l.1 .1a.82 .82 0 0 0-.1 1.1h.2l.7-.7 .2 .1-.7 .8v.8h-6.1zM112.8 104.3l.2-.1 .1 .2-.3 .1zM148.2 101.2h1.2l.2-.6v2.7l-.2-.6h-1.2v-1.2h.3v1h.9l.1-.2-.1-.3 .1-.4-.1-.1h-1.2z"/>
</g>
<g fill="#fff" stroke="#fff" stroke-width=".21">
<circle cx="115.1" cy="97" r=".17"/>
<circle cx="127" cy="102.1" r=".17"/>
<circle cx="140.2" cy="99.1" r=".17"/>
<circle cx="137.7" cy="101.3" r=".17"/>
<circle cx="127" cy="110.2" r=".17"/>
<circle cx="133.9" cy="86.6" r=".17"/>
<circle cx="137.2" cy="86.6" r=".17"/>
<circle cx="141.7" cy="73.7" r=".17"/>
<circle cx="127" cy="97.5" r=".17"/>
<circle cx="114" cy="95" r=".17"/>
<circle cx="123.2" cy="105.9" r=".17"/>
<circle cx="135.1" cy="82.3" r=".17"/>
<circle cx="116.8" cy="86.1" r=".17"/>
<circle cx="118.1" cy="72.4" r=".17"/>
<circle cx="109.5" cy="98.8" r=".17"/>
<circle cx="110.5" cy="95.2" r=".17"/>
<circle cx="109.2" cy="114.8" r=".17"/>
<circle cx="117.6" cy="112" r=".17"/>
<circle cx="140" cy="106.7" r=".17"/>
<circle cx="141.7" cy="99.1" r=".17"/>
<circle cx="144.8" cy="97.8" r=".17"/>
<circle cx="113" cy="90.9" r=".17"/>
<circle cx="104.9" cy="68.8" r=".17"/>
<circle cx="104.9" cy="71.4" r=".17"/>
<circle cx="143.5" cy="88.4" r=".17"/>
<circle cx="130.6" cy="98.8" r=".17"/>
<circle cx="135.1" cy="99.1" r=".17"/>
<circle cx="112" cy="81" r=".17"/>
<circle cx="139.7" cy="68.8" r=".17"/>
<circle cx="135.1" cy="68.8" r=".17"/>
<circle cx="120.6" cy="87.4" r=".17"/>
<circle cx="122.2" cy="80.3" r=".17"/>
<circle cx="100.3" cy="115.3" r=".17"/>
<circle cx="118.1" cy="77.5" r=".17"/>
<circle cx="133.9" cy="84.3" r=".17"/>
<circle cx="139.4" cy="83.6" r=".17"/>
<circle cx="144.3" cy="84.3" r=".17"/>
<circle cx="133.9" cy="70.1" r=".17"/>
<circle cx="125.2" cy="78.7" r=".17"/>
<circle cx="109" cy="70.1" r=".17"/>
<circle cx="107.2" cy="80.3" r=".17"/>
<circle cx="114.8" cy="101.8" r=".17"/>
<circle cx="115.6" cy="98.3" r=".17"/>
<circle cx="125.5" cy="110.5" r=".17"/>
<circle cx="119.6" cy="107.7" r=".17"/>
<circle cx="119.6" cy="113.5" r=".17"/>
<circle cx="123.4" cy="80.3" r=".17"/>
<circle cx="121.2" cy="88.9" r=".17"/>
<circle cx="146" cy="99.1" r=".17"/>
<circle cx="140" cy="101.1" r=".17"/>
<circle cx="149.6" cy="89.9" r=".17"/>
<circle cx="149.4" cy="99.3" r=".17"/>
<circle cx="149.1" cy="78.2" r=".17"/>
<circle cx="149.6" cy="82.3" r=".17"/>
<circle cx="147.1" cy="101.1" r=".17"/>
<circle cx="146" cy="86.1" r=".17"/>
<circle cx="145.3" cy="85.1" r=".17"/>
<circle cx="147.1" cy="106.4" r=".17"/>
<circle cx="143" cy="84.3" r=".17"/>
<circle cx="143" cy="86.6" r=".17"/>
<circle cx="143.8" cy="99.8" r=".17"/>
<circle cx="143.8" cy="103.4" r=".17"/>
<circle cx="148.1" cy="95.5" r=".17"/>
<circle cx="145.8" cy="83.6" r=".17"/>
<circle cx="143" cy="82.8" r=".17"/>
<circle cx="144.5" cy="82.8" r=".17"/>
<circle cx="148.8" cy="89.1" r=".17"/>
<circle cx="139.4" cy="81.8" r=".17"/>
<circle cx="127.5" cy="82.5" r=".17"/>
<circle cx="122.9" cy="82.5" r=".17"/>
<circle cx="128" cy="81.8" r=".17"/>
<circle cx="123.4" cy="81.8" r=".17"/>
<circle cx="124.5" cy="91.4" r=".17"/>
<circle cx="120.9" cy="89.9" r=".17"/>
<circle cx="124" cy="92.5" r=".17"/>
<circle cx="120.4" cy="90.7" r=".17"/>
<circle cx="124.5" cy="93.2" r=".17"/>
<circle cx="120.4" cy="91.7" r=".17"/>
<circle cx="104" cy="92.6" r=".15"/>
<circle cx="107.2" cy="92.6" r=".15"/>
<circle cx="104" cy="91.8" r=".15"/>
<circle cx="107.2" cy="91.8" r=".15"/>
<circle cx="113" cy="89.9" r=".17"/>
<circle cx="104" cy="91.1" r=".15"/>
<circle cx="107.2" cy="91.1" r=".15"/>
<circle cx="104" cy="90.2" r=".15"/>
<circle cx="107.2" cy="90.2" r=".15"/>
<circle cx="113" cy="87.1" r=".17"/>
<circle cx="104" cy="88.8" r=".15"/>
<circle cx="107.2" cy="88.8" r=".15"/>
<circle cx="104" cy="88" r=".15"/>
<circle cx="107.2" cy="88" r=".15"/>
<circle cx="104" cy="87.2" r=".15"/>
<circle cx="107.2" cy="87.2" r=".15"/>
<circle cx="104" cy="86.5" r=".15"/>
<circle cx="107.2" cy="86.5" r=".15"/>
<circle cx="104" cy="85.1" r=".15"/>
<circle cx="107.2" cy="85.1" r=".15"/>
<circle cx="104" cy="84.2" r=".15"/>
<circle cx="107.2" cy="84.2" r=".15"/>
<circle cx="104" cy="83.4" r=".15"/>
<circle cx="107.2" cy="83.4" r=".15"/>
<circle cx="104" cy="82.5" r=".15"/>
<circle cx="107.2" cy="82.5" r=".15"/>
<circle cx="108.7" cy="81.5" r=".17"/>
<circle cx="103.1" cy="81.5" r=".17"/>
<circle cx="104" cy="78.4" r=".15"/>
<circle cx="107.2" cy="78.4" r=".15"/>
<circle cx="104" cy="77.6" r=".15"/>
<circle cx="107.2" cy="77.6" r=".15"/>
<circle cx="104" cy="76.8" r=".15"/>
<circle cx="107.2" cy="76.8" r=".15"/>
<circle cx="104" cy="75.9" r=".15"/>
<circle cx="107.2" cy="75.9" r=".15"/>
<circle cx="104" cy="74.5" r=".15"/>
<circle cx="107.2" cy="74.5" r=".15"/>
<circle cx="104" cy="73.8" r=".15"/>
<circle cx="107.2" cy="73.8" r=".15"/>
<circle cx="104" cy="73" r=".15"/>
<circle cx="107.2" cy="73" r=".15"/>
<circle cx="104" cy="72.1" r=".15"/>
<circle cx="107.2" cy="72.1" r=".15"/>
<circle cx="148.1" cy="80.5" r=".17"/>
<circle cx="148.1" cy="88.9" r=".17"/>
<circle cx="144.5" cy="100.3" r=".17"/>
<circle cx="144.5" cy="101.8" r=".17"/>
<circle cx="145.3" cy="99.8" r=".17"/>
<circle cx="146.3" cy="103.1" r=".17"/>
<circle cx="149.6" cy="107.4" r=".17"/>
<circle cx="146.8" cy="93.5" r=".17"/>
<circle cx="147.3" cy="80" r=".17"/>
<circle cx="148.8" cy="96.3" r=".17"/>
<circle cx="127.5" cy="93.2" r=".17"/>
<circle cx="112" cy="95.8" r=".17"/>
<circle cx="122.2" cy="99.6" r=".17"/>
<circle cx="122.2" cy="102.1" r=".17"/>
<circle cx="109.6" cy="104.1" r=".17"/>
<circle cx="118.1" cy="104.9" r=".17"/>
<circle cx="118.9" cy="99.1" r=".17"/>
<circle cx="118.9" cy="100.6" r=".17"/>
<circle cx="105.9" cy="101.6" r=".17"/>
<circle cx="118.1" cy="98.3" r=".17"/>
<circle cx="119.6" cy="98.3" r=".17"/>
<circle cx="114.8" cy="100.6" r=".17"/>
<circle cx="116.3" cy="101.3" r=".17"/>
<circle cx="114.8" cy="105.7" r=".17"/>
<circle cx="116.3" cy="105.7" r=".17"/>
<circle cx="121.2" cy="99.1" r=".17"/>
<circle cx="121.2" cy="101.6" r=".17"/>
<circle cx="120.1" cy="96.1" r=".17"/>
<circle cx="118.9" cy="83.9" r=".17"/>
<circle cx="103.3" cy="104.1" r=".17"/>
<circle cx="114.8" cy="103.1" r=".17"/>
<circle cx="141.7" cy="94.2" r=".17"/>
<circle cx="138.2" cy="89.7" r=".17"/>
<circle cx="138.4" cy="92.5" r=".17"/>
<circle cx="135.1" cy="103.8" r=".17"/>
<circle cx="138.4" cy="91.2" r=".17"/>
<circle cx="134.1" cy="103.8" r=".17"/>
<circle cx="125.7" cy="97.3" r=".17"/>
<circle cx="128.5" cy="93.2" r=".17"/>
<circle cx="88.8" cy="112.8" r=".17"/>
<circle cx="146.6" cy="112.8" r=".17"/>
<circle cx="146.6" cy="72.8" r=".17"/>
<circle cx="88.8" cy="72.8" r=".17"/>
<circle cx="104.6" cy="95.2" r=".17"/>
<circle cx="107.2" cy="95.2" r=".17"/>
<circle cx="104.6" cy="97.8" r=".17"/>
<circle cx="107.2" cy="97.8" r=".17"/>
<circle cx="104.6" cy="100.3" r=".17"/>
<circle cx="107.2" cy="100.3" r=".17"/>
<circle cx="104.6" cy="102.9" r=".17"/>
<circle cx="107.2" cy="102.9" r=".17"/>
<circle cx="104.6" cy="105.4" r=".17"/>
<circle cx="107.2" cy="105.4" r=".17"/>
<circle cx="111.3" cy="99.3" r=".17"/>
<circle cx="113.3" cy="99.3" r=".17"/>
<circle cx="112.3" cy="106.9" r=".17"/>
<circle cx="108.5" cy="111.2" r=".17"/>
<circle cx="106" cy="111.2" r=".17"/>
<circle cx="98.6" cy="113" r=".17"/>
<circle cx="96" cy="113" r=".17"/>
<circle cx="98.6" cy="110.5" r=".17"/>
<circle cx="96" cy="110.5" r=".17"/>
<circle cx="98.6" cy="107.9" r=".17"/>
<circle cx="96" cy="107.9" r=".17"/>
<circle cx="98.6" cy="105.4" r=".17"/>
<circle cx="96" cy="105.4" r=".17"/>
<circle cx="98.6" cy="102.9" r=".17"/>
<circle cx="96" cy="102.9" r=".17"/>
<circle cx="98.6" cy="100.3" r=".17"/>
<circle cx="96" cy="100.3" r=".17"/>
<circle cx="98.6" cy="97.8" r=".17"/>
<circle cx="96" cy="97.8" r=".17"/>
<circle cx="98.6" cy="95.2" r=".17"/>
<circle cx="96" cy="95.2" r=".17"/>
<circle cx="98.6" cy="92.7" r=".17"/>
<circle cx="96" cy="92.7" r=".17"/>
<circle cx="98.6" cy="90.2" r=".17"/>
<circle cx="96" cy="90.2" r=".17"/>
<circle cx="98.6" cy="87.6" r=".17"/>
<circle cx="96" cy="87.6" r=".17"/>
<circle cx="98.6" cy="85.1" r=".17"/>
<circle cx="96" cy="85.1" r=".17"/>
<circle cx="98.6" cy="82.5" r=".17"/>
<circle cx="96" cy="82.5" r=".17"/>
<circle cx="98.6" cy="80" r=".17"/>
<circle cx="96" cy="80" r=".17"/>
<circle cx="98.6" cy="77.5" r=".17"/>
<circle cx="96" cy="77.5" r=".17"/>
<circle cx="98.6" cy="74.9" r=".17"/>
<circle cx="96" cy="74.9" r=".17"/>
<circle cx="98.6" cy="72.4" r=".17"/>
<circle cx="96" cy="72.4" r=".17"/>
<circle cx="116.8" cy="75.7" r=".17"/>
<circle cx="119.4" cy="75.7" r=".17"/>
<circle cx="121.9" cy="75.7" r=".17"/>
<circle cx="124.5" cy="75.7" r=".17"/>
<circle cx="127" cy="75.7" r=".17"/>
<circle cx="129.5" cy="75.7" r=".17"/>
<circle cx="138.2" cy="111.2" r=".17"/>
<circle cx="135.7" cy="111.2" r=".17"/>
<circle cx="133.2" cy="111.2" r=".17"/>
<circle cx="130.7" cy="111.2" r=".18"/>
</g>
</svg>
